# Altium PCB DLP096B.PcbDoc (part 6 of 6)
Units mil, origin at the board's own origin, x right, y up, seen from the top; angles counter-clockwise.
Board outline 4950 x 3159.45 mil, 8 copper layers (Top Layer, GND1, SIGNAL1, POWER1, POWER2, SIGNAL2, GND2, Bottom Layer), stack 60.4 mil thick; 327 components, 222 nets, 1374 pads, 853 vias.

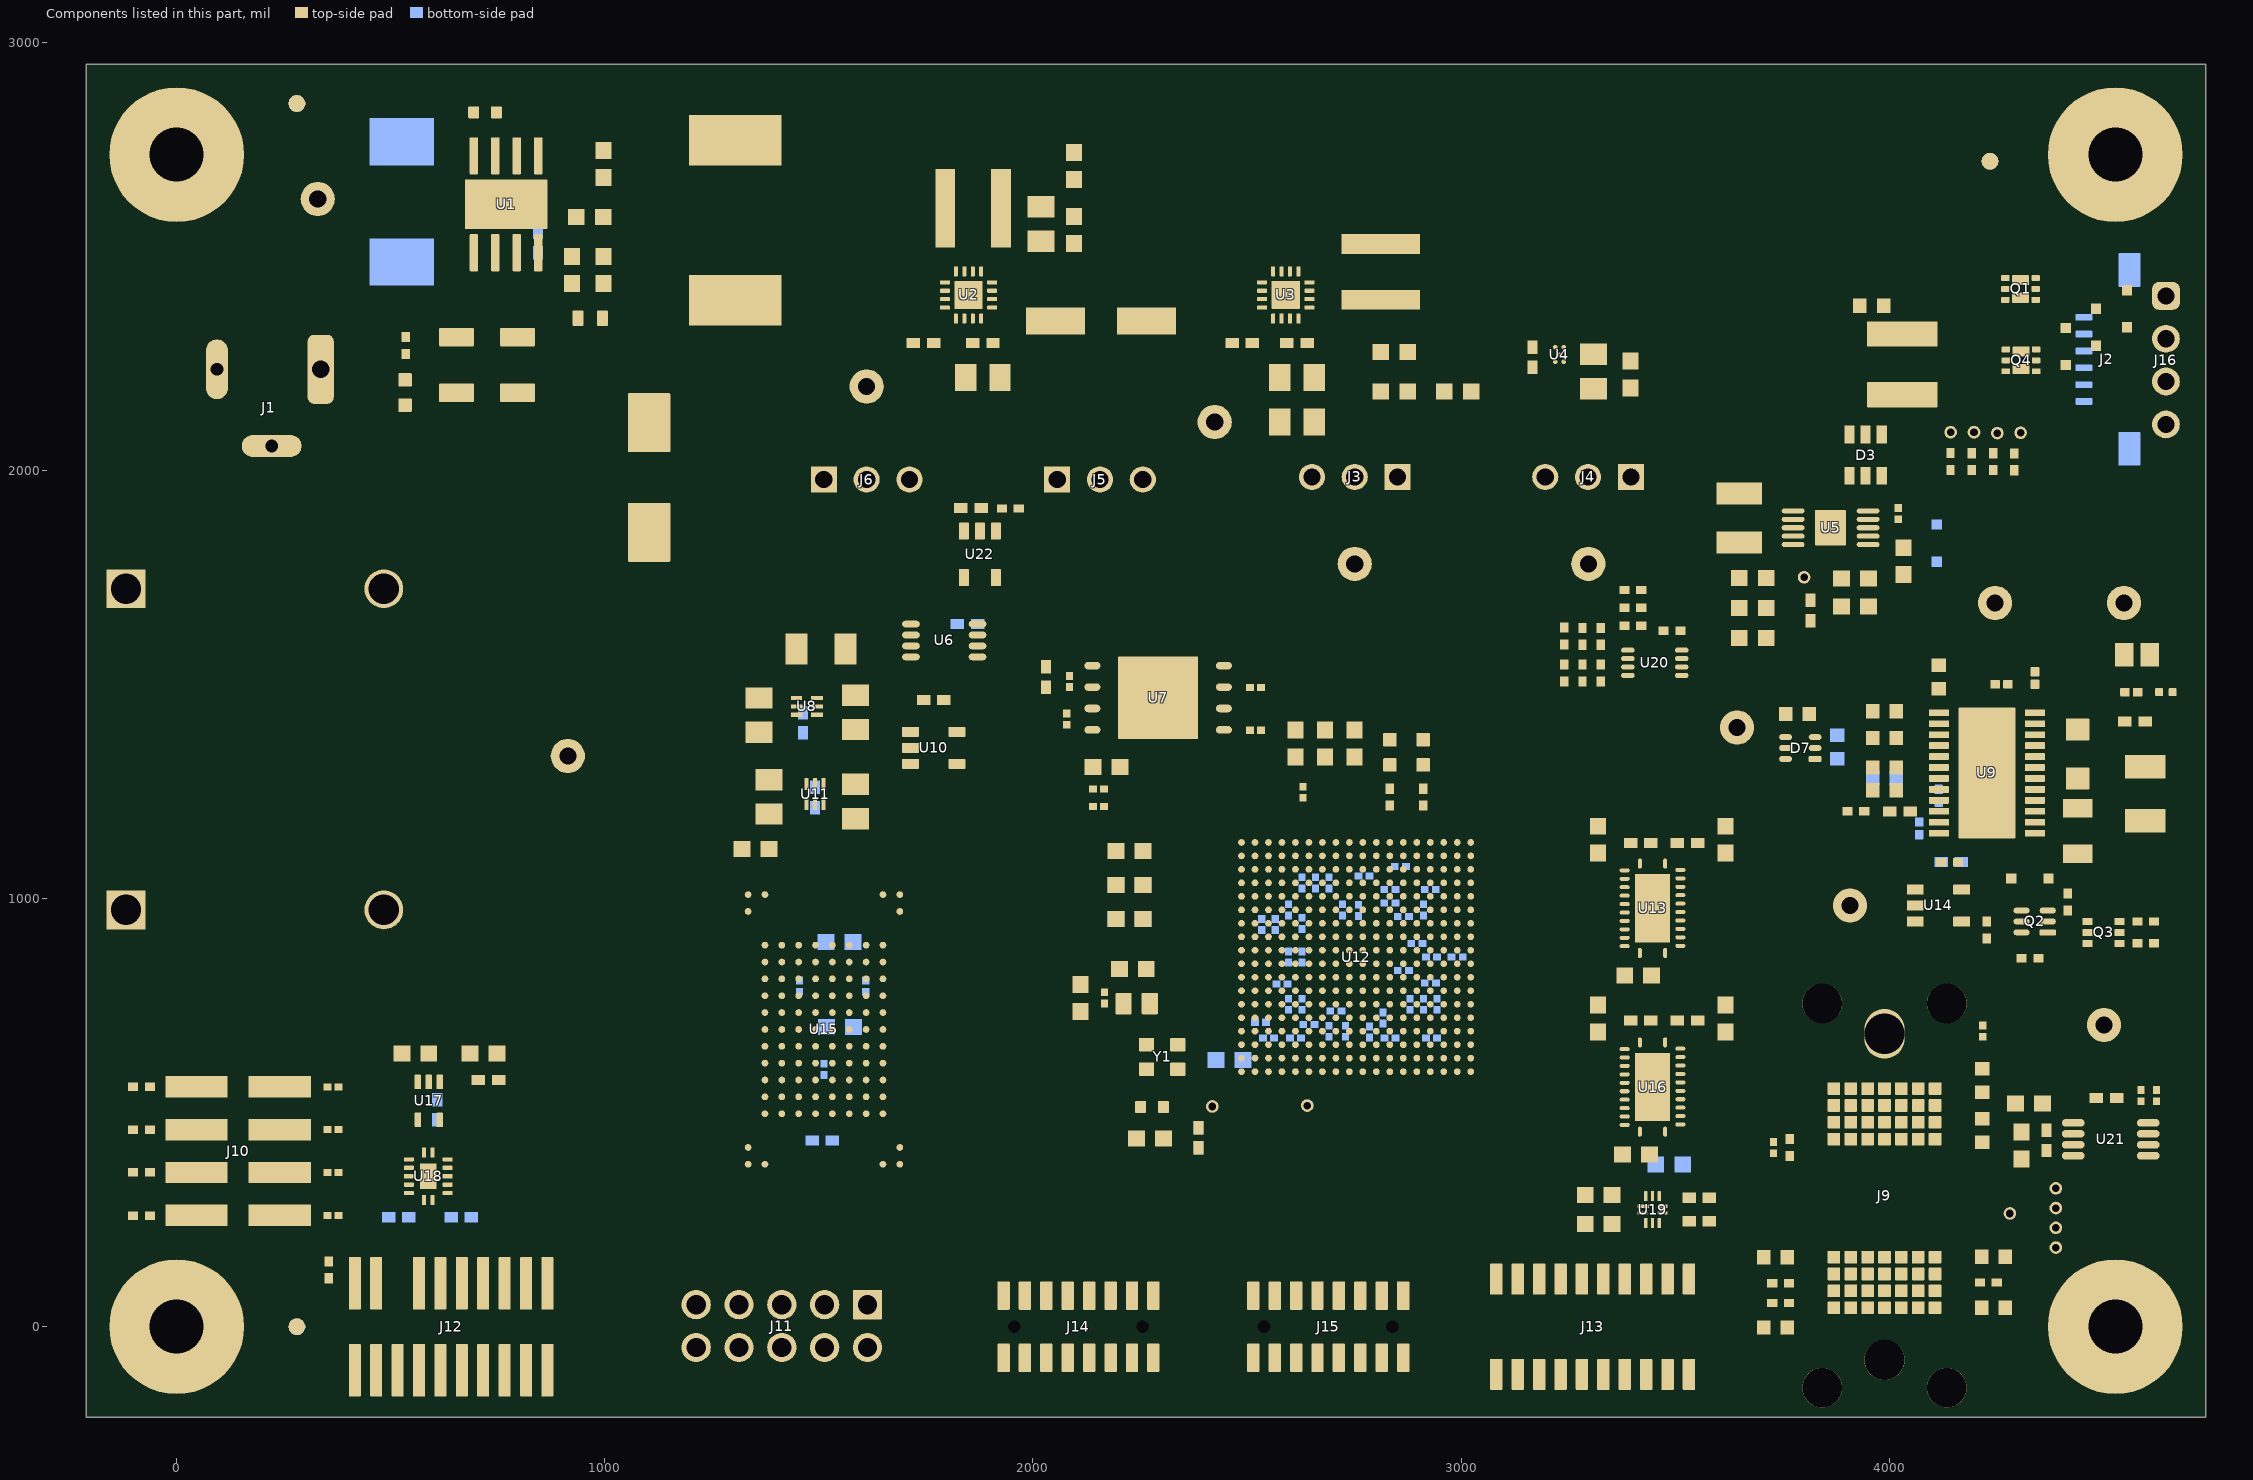
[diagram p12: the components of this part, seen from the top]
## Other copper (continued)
POWER1:
  pour cut-out: 531.25,2068.57 533.66,2068.71 536.04,2069.15 538.34,2069.87 541.6,2071.45 542.62,2072.11 543.59,2072.83 545.4,2074.43 546.23,2075.31 547,2076.24 548.37,2078.23 548.97,2079.28 549.49,2080.36 550.35,2082.62 550.68,2083.79 551.22,2087.37 551.26,2088.58 551.11,2090.99 550.93,2092.18 550.68,2093.37 550.35,2094.53 549.96,2095.67 549.49,2096.79 548.97,2097.88 548.37,2098.93 547.72,2099.94 547,2100.92 546.23,2101.85 544.52,2103.55 543.59,2104.33 542.62,2105.04 541.6,2105.7 540.55,2106.29 539.46,2106.82 538.34,2107.29 533.66,2108.44 531.25,2108.59 528.84,2108.44 525.3,2107.68 524.15,2107.29 521.95,2106.29 520.9,2105.7 519.88,2105.04 518.91,2104.33 517.1,2102.73 516.27,2101.85 515.5,2100.92 514.78,2099.94 513.53,2097.88 513,2096.79 512.54,2095.67 511.57,2092.18 511.28,2089.78 511.24,2088.58 511.39,2086.16 511.82,2083.79 512.54,2081.48 513,2080.36 513.53,2079.28 514.78,2077.21 516.27,2075.31 517.1,2074.43 517.98,2073.6 519.88,2072.11 520.9,2071.45 521.95,2070.86 524.15,2069.87 525.3,2069.47 526.46,2069.15 528.84,2068.71 530.04,2068.6
  pour cut-out: 531.25,1972.29 533.66,1972.44 536.04,1972.87 538.34,1973.59 541.6,1975.18 542.62,1975.83 543.59,1976.55 545.4,1978.15 546.23,1979.03 547,1979.96 548.37,1981.95 548.97,1983 549.49,1984.09 550.35,1986.35 550.68,1987.51 551.22,1991.09 551.26,1992.3 551.11,1994.71 550.93,1995.91 550.68,1997.09 550.35,1998.25 549.96,1999.4 549.49,2000.51 548.97,2001.6 548.37,2002.65 547.72,2003.67 547,2004.64 546.23,2005.57 544.52,2007.28 543.59,2008.05 542.62,2008.77 541.6,2009.42 540.55,2010.02 539.46,2010.55 538.34,2011.01 533.66,2012.16 531.25,2012.31 528.84,2012.16 525.3,2011.4 524.15,2011.01 521.95,2010.02 520.9,2009.42 519.88,2008.77 518.91,2008.05 517.1,2006.45 516.27,2005.57 515.5,2004.64 514.78,2003.67 513.53,2001.6 513,2000.51 512.54,1999.4 511.57,1995.91 511.28,1993.51 511.24,1992.3 511.39,1989.89 511.82,1987.51 512.54,1985.21 513,1984.09 513.53,1983 514.78,1980.93 516.27,1979.03 517.1,1978.15 517.98,1977.32 519.88,1975.83 520.9,1975.18 521.95,1974.58 524.15,1973.59 525.3,1973.2 526.46,1972.87 528.84,1972.44 530.04,1972.33
  pour cut-out: 525.76,530.44 528.17,530.58 530.55,531.02 532.85,531.74 536.11,533.32 537.12,533.98 538.1,534.69 539.91,536.3 540.73,537.18 541.51,538.1 542.88,540.09 543.47,541.15 544,542.23 544.86,544.49 545.18,545.66 545.73,549.24 545.77,550.44 545.62,552.86 545.44,554.05 545.18,555.23 544.86,556.4 544.47,557.54 544,558.66 543.47,559.74 542.88,560.8 542.22,561.81 541.51,562.78 540.73,563.71 539.03,565.42 538.1,566.2 537.12,566.91 536.11,567.57 535.06,568.16 533.97,568.69 532.85,569.15 528.17,570.31 525.76,570.45 523.34,570.31 519.8,569.55 518.66,569.15 516.46,568.16 515.41,567.57 514.39,566.91 513.42,566.2 511.61,564.59 510.78,563.71 510.01,562.78 509.29,561.81 508.04,559.74 507.51,558.66 507.05,557.54 506.08,554.05 505.78,551.65 505.75,550.44 505.89,548.03 506.33,545.66 507.05,543.35 507.51,542.23 508.04,541.15 509.29,539.08 510.78,537.18 511.61,536.3 512.49,535.47 514.39,533.98 515.41,533.32 516.46,532.73 518.66,531.74 519.8,531.34 520.97,531.02 523.34,530.58 524.55,530.47
  pour cut-out: 4164.06,1177.96 4164.06,1421.8 4178.52,1436.25 4271.31,1436.25 4292.31,1415.25 4292.31,1164.9 4277.78,1150.37 4228.17,1150.37 4228.13,1150.33 4227.5,1150.95 4177.9,1150.95 4163.91,1164.94 4163.91,1175.18
  pour cut-out: 2567.16,2413.07 2569.57,2413.22 2571.95,2413.65 2574.26,2414.37 2577.51,2415.96 2578.53,2416.61 2579.5,2417.33 2581.31,2418.93 2582.14,2419.81 2582.91,2420.74 2584.28,2422.73 2584.88,2423.78 2585.41,2424.87 2586.26,2427.13 2586.59,2428.29 2587.13,2431.87 2587.17,2433.08 2587.02,2435.49 2586.84,2436.69 2586.59,2437.87 2586.26,2439.03 2585.87,2440.17 2585.41,2441.29 2584.88,2442.38 2584.28,2443.43 2583.63,2444.45 2582.91,2445.42 2582.14,2446.35 2580.43,2448.06 2579.5,2448.83 2578.53,2449.55 2577.51,2450.2 2576.46,2450.8 2575.37,2451.33 2574.26,2451.79 2569.57,2452.94 2567.16,2453.09 2564.75,2452.94 2561.21,2452.18 2560.06,2451.79 2557.86,2450.8 2556.81,2450.2 2555.79,2449.55 2554.82,2448.83 2553.01,2447.23 2552.18,2446.35 2551.41,2445.42 2550.69,2444.45 2549.44,2442.38 2548.91,2441.29 2548.45,2440.17 2547.48,2436.69 2547.19,2434.29 2547.15,2433.08 2547.3,2430.67 2547.73,2428.29 2548.45,2425.98 2548.91,2424.87 2549.44,2423.78 2550.69,2421.71 2552.18,2419.81 2553.01,2418.93 2553.89,2418.1 2555.79,2416.61 2556.81,2415.96 2557.86,2415.36 2560.06,2414.37 2561.21,2413.98 2562.37,2413.65 2564.75,2413.22 2565.95,2413.11
  pour cut-out: 2567.16,2366.61 2569.57,2366.76 2571.95,2367.19 2574.26,2367.91 2577.51,2369.5 2578.53,2370.16 2579.5,2370.87 2581.31,2372.47 2582.14,2373.35 2582.91,2374.28 2584.28,2376.27 2584.88,2377.32 2585.41,2378.41 2586.26,2380.67 2586.59,2381.83 2587.13,2385.41 2587.17,2386.62 2587.02,2389.03 2586.84,2390.23 2586.59,2391.41 2586.26,2392.58 2585.87,2393.72 2585.41,2394.83 2584.88,2395.92 2584.28,2396.97 2583.63,2397.99 2582.91,2398.96 2582.14,2399.89 2580.43,2401.6 2579.5,2402.37 2578.53,2403.09 2577.51,2403.75 2576.46,2404.34 2575.37,2404.87 2574.26,2405.33 2569.57,2406.49 2567.16,2406.63 2564.75,2406.49 2561.21,2405.73 2560.06,2405.33 2557.86,2404.34 2556.81,2403.75 2555.79,2403.09 2554.82,2402.37 2553.01,2400.77 2552.18,2399.89 2551.41,2398.96 2550.69,2397.99 2549.44,2395.92 2548.91,2394.83 2548.45,2393.72 2547.48,2390.23 2547.19,2387.83 2547.15,2386.62 2547.3,2384.21 2547.73,2381.83 2548.45,2379.53 2548.91,2378.41 2549.44,2377.32 2550.69,2375.26 2552.18,2373.35 2553.01,2372.47 2553.89,2371.65 2555.79,2370.16 2556.81,2369.5 2557.86,2368.91 2560.06,2367.91 2561.21,2367.52 2562.37,2367.19 2564.75,2366.76 2565.95,2366.65
  pour cut-out: 2613.62,2366.61 2616.03,2366.76 2618.41,2367.19 2620.71,2367.91 2623.97,2369.5 2624.98,2370.16 2625.96,2370.87 2627.77,2372.47 2628.59,2373.35 2629.37,2374.28 2630.74,2376.27 2631.33,2377.32 2631.86,2378.41 2632.72,2380.67 2633.04,2381.83 2633.59,2385.41 2633.63,2386.62 2633.48,2389.03 2633.3,2390.23 2633.04,2391.41 2632.72,2392.58 2632.33,2393.72 2631.86,2394.83 2631.33,2395.92 2630.74,2396.97 2630.08,2397.99 2629.37,2398.96 2628.59,2399.89 2626.89,2401.6 2625.96,2402.37 2624.98,2403.09 2623.97,2403.75 2622.92,2404.34 2621.83,2404.87 2620.71,2405.33 2616.03,2406.49 2613.62,2406.63 2611.2,2406.49 2607.66,2405.73 2606.52,2405.33 2604.32,2404.34 2603.27,2403.75 2602.25,2403.09 2601.28,2402.37 2599.47,2400.77 2598.64,2399.89 2597.87,2398.96 2597.15,2397.99 2595.9,2395.92 2595.37,2394.83 2594.91,2393.72 2593.94,2390.23 2593.64,2387.83 2593.61,2386.62 2593.75,2384.21 2594.19,2381.83 2594.91,2379.53 2595.37,2378.41 2595.9,2377.32 2597.15,2375.26 2598.64,2373.35 2599.47,2372.47 2600.35,2371.65 2602.25,2370.16 2603.27,2369.5 2604.32,2368.91 2606.52,2367.91 2607.66,2367.52 2608.83,2367.19 2611.2,2366.76 2612.41,2366.65
  pour cut-out: 2613.62,2413.07 2616.03,2413.22 2618.41,2413.65 2620.71,2414.37 2623.97,2415.96 2624.98,2416.61 2625.96,2417.33 2627.77,2418.93 2628.59,2419.81 2629.37,2420.74 2630.74,2422.73 2631.33,2423.78 2631.86,2424.87 2632.72,2427.13 2633.04,2428.29 2633.59,2431.87 2633.63,2433.08 2633.48,2435.49 2633.3,2436.69 2633.04,2437.87 2632.72,2439.03 2632.33,2440.17 2631.86,2441.29 2631.33,2442.38 2630.74,2443.43 2630.08,2444.45 2629.37,2445.42 2628.59,2446.35 2626.89,2448.06 2625.96,2448.83 2624.98,2449.55 2623.97,2450.2 2622.92,2450.8 2621.83,2451.33 2620.71,2451.79 2616.03,2452.94 2613.62,2453.09 2611.2,2452.94 2607.66,2452.18 2606.52,2451.79 2604.32,2450.8 2603.27,2450.2 2602.25,2449.55 2601.28,2448.83 2599.47,2447.23 2598.64,2446.35 2597.87,2445.42 2597.15,2444.45 2595.9,2442.38 2595.37,2441.29 2594.91,2440.17 2593.94,2436.69 2593.64,2434.29 2593.61,2433.08 2593.75,2430.67 2594.19,2428.29 2594.91,2425.98 2595.37,2424.87 2595.9,2423.78 2597.15,2421.71 2598.64,2419.81 2599.47,2418.93 2600.35,2418.1 2602.25,2416.61 2603.27,2415.96 2604.32,2415.36 2606.52,2414.37 2607.66,2413.98 2608.83,2413.65 2611.2,2413.22 2612.41,2413.11
  pour cut-out: 1922.97,2133.39 1925.38,2133.53 1927.76,2133.97 1930.06,2134.69 1933.32,2136.27 1934.34,2136.93 1935.31,2137.65 1937.12,2139.25 1937.95,2140.13 1938.72,2141.06 1940.09,2143.05 1940.69,2144.1 1941.21,2145.18 1942.07,2147.44 1942.4,2148.61 1942.94,2152.19 1942.98,2153.4 1942.83,2155.81 1942.65,2157 1942.4,2158.19 1942.07,2159.35 1941.68,2160.49 1941.21,2161.61 1940.69,2162.7 1940.09,2163.75 1939.44,2164.76 1938.72,2165.74 1937.95,2166.67 1936.24,2168.37 1935.31,2169.15 1934.34,2169.86 1933.32,2170.52 1932.27,2171.11 1931.18,2171.64 1930.06,2172.11 1925.38,2173.26 1922.97,2173.41 1920.56,2173.26 1917.02,2172.5 1915.87,2172.11 1913.67,2171.11 1912.62,2170.52 1911.6,2169.86 1910.63,2169.15 1908.82,2167.55 1907.99,2166.67 1907.22,2165.74 1906.5,2164.76 1905.25,2162.7 1904.72,2161.61 1904.26,2160.49 1903.29,2157 1903,2154.6 1902.96,2153.4 1903.11,2150.99 1903.54,2148.61 1904.26,2146.3 1904.72,2145.18 1905.25,2144.1 1906.5,2142.03 1907.99,2140.13 1908.82,2139.25 1909.7,2138.42 1911.6,2136.93 1912.62,2136.27 1913.67,2135.68 1915.87,2134.69 1917.02,2134.29 1918.18,2133.97 1920.56,2133.53 1921.76,2133.42
  pour cut-out: 1947.7,2262.04 1950.11,2262.19 1952.48,2262.62 1954.79,2263.34 1958.05,2264.93 1959.06,2265.58 1960.04,2266.3 1961.84,2267.9 1962.67,2268.78 1963.45,2269.71 1964.82,2271.7 1965.41,2272.75 1965.94,2273.84 1966.8,2276.1 1967.12,2277.26 1967.67,2280.84 1967.71,2282.05 1967.56,2284.46 1967.38,2285.66 1967.12,2286.84 1966.8,2288 1966.4,2289.15 1965.94,2290.26 1965.41,2291.35 1964.82,2292.4 1964.16,2293.42 1963.45,2294.39 1962.67,2295.32 1960.96,2297.03 1960.04,2297.8 1959.06,2298.52 1958.05,2299.17 1956.99,2299.77 1955.91,2300.3 1954.79,2300.76 1950.11,2301.91 1947.7,2302.06 1945.28,2301.91 1941.74,2301.15 1940.6,2300.76 1938.4,2299.77 1937.34,2299.17 1936.33,2298.52 1935.36,2297.8 1933.55,2296.2 1932.72,2295.32 1931.95,2294.39 1931.23,2293.42 1929.98,2291.35 1929.45,2290.26 1928.99,2289.15 1928.01,2285.66 1927.72,2283.26 1927.69,2282.05 1927.83,2279.64 1928.27,2277.26 1928.99,2274.95 1929.45,2273.84 1929.98,2272.75 1931.23,2270.68 1932.72,2268.78 1933.55,2267.9 1934.43,2267.07 1936.33,2265.58 1937.34,2264.93 1938.4,2264.33 1940.6,2263.34 1941.74,2262.95 1942.91,2262.62 1945.28,2262.19 1946.49,2262.08
  pour cut-out: 1416.04,1418.24 1418.45,1418.39 1420.83,1418.82 1423.14,1419.54 1426.39,1421.12 1427.41,1421.78 1428.38,1422.5 1430.19,1424.1 1431.02,1424.98 1431.79,1425.91 1433.17,1427.9 1433.76,1428.95 1434.29,1430.04 1435.15,1432.3 1435.47,1433.46 1436.01,1437.04 1436.05,1438.25 1435.91,1440.66 1435.72,1441.86 1435.47,1443.04 1435.15,1444.2 1434.75,1445.34 1434.29,1446.46 1433.76,1447.55 1433.17,1448.6 1432.51,1449.61 1431.79,1450.59 1431.02,1451.52 1429.31,1453.23 1428.38,1454 1427.41,1454.72 1426.39,1455.37 1425.34,1455.97 1424.25,1456.49 1423.14,1456.96 1418.45,1458.11 1416.04,1458.26 1413.63,1458.11 1410.09,1457.35 1408.95,1456.96 1406.74,1455.97 1405.69,1455.37 1404.68,1454.72 1403.7,1454 1401.89,1452.4 1401.07,1451.52 1400.29,1450.59 1399.57,1449.61 1398.32,1447.55 1397.8,1446.46 1397.33,1445.34 1396.36,1441.86 1396.07,1439.46 1396.03,1438.25 1396.18,1435.84 1396.61,1433.46 1397.33,1431.15 1397.8,1430.04 1398.32,1428.95 1399.57,1426.88 1401.07,1424.98 1401.89,1424.1 1402.77,1423.27 1404.68,1421.78 1405.69,1421.12 1406.74,1420.53 1408.95,1419.54 1410.09,1419.15 1411.25,1418.82 1413.63,1418.39 1414.83,1418.28
  pour cut-out: 2163.93,504.84 2163.93,423.37 2182.57,423.37 2186.04,426.84 2186.04,482.73
  pour cut-out: 4251.1,843.02 4204.31,843.02 4204.5,843.21 4204.5,851.48 4204.92,851.9 4251.14,851.9
  text "4" at 2588.44,2743.77 h60
  text "POWER1" at 376.89,-1071.84 h60
POWER2:
  text "5" at 2588.44,2743.77 h60
  text "POWER2" at 371.65,-1073.59 h60
Bottom Layer:
  text "8" at 2588.44,2743.77 h60
  text ".Layer_Name" at 366,-1069.49 h60

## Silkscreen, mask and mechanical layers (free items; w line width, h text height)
Top Overlay:
  circle w10: c1879.46,2490.68 r1.81
  circle w10: c4380.04,1152.3 r4.87
  circle w10: c2619.42,2494.23 r3
  circle w10: c693.58,2446.43 r4.87
  circle w10: c4536.63,865.5 r3
  circle w10: c3531.53,-166.36 r4.87
  circle w15: c-96.35,2453.46 r10
  circle w10: c4439.56,1444.76 r4.87
  circle w10: c3982.04,2122.81 r4.87
  lines w6.1: 883.26,2385.63 959.52,2385.63 969.69,2395.8 ; 3786.67,977.78 3840.7,977.78 ; 4567.9,706.4 4637.9,706.4
  lines w6.5: 2004.06,738.47 2013.27,729.27 2070.31,729.27 ; 2750,1903.55 2750,1925.06 ; 3295,1903.55 3295,1925.06 ; 3924.39,1326.74 3924.39,1311.86 3932.25,1304 ; 3937.71,1528.63 3929.11,1520.03 3929.11,1473.96 3939.91,1463.15 ; 3944.99,1564.84 3963.78,1583.63 3963.78,1642.19 ; 4238.32,13.92 4238.32,-94.35 4252.17,-108.21
  text "'.PRJ_Number'.PCB_Rev" at 3681.49,2682.51 h108.27
  text "12V" at 286.81,2529.82 h30
  text "LED" at 4600.93,2471.4 h30
  text "R" at 4588.17,2278.75 h30 r90
  text "12V" at 379.08,2243.8 h30
  text "+" at 1171.78,2200.63 h70
  text "G" at 4588.17,2185.05 h30 r90
  text "S_EN" at 4170.21,2107.79 h23 r90
  text "R_EN" at 4213.37,2107.79 h23 r90
  text "B_EN" at 4256.54,2107.79 h23 r90
  text "G_EN" at 4299.71,2107.79 h23 r90
  text "B" at 4588.17,2092.67 h30 r90
  text "5V" at 1583.7,2091.55 h30
  text "3V3" at 2378.07,2010.42 h30
  text "GND" at 2587.39,1940.16 h30 r90
  text "GND" at 3136.28,1934.41 h30 r90
  text "1V2_OB" at 2957.89,1897.16 h30 r90
  text "1V2_EXT" at 2644.1,1850.85 h30
  text "1.8V_DMD_EXT" at 3090.98,1850.3 h30
  text "GND" at 2275.45,1826.96 h30 r90
  text "GND" at 1729.49,1826.09 h30 r90
  text "1.8V_DMD_OB" at 3503.43,1825.38 h30 r90
  text "5V_OB" at 1533.14,1768.43 h30 r90
  text "VOFFSET" at 4452.84,1755.46 h30
  text "VBIAS" at 4176.38,1752.8 h30
  text "1V8" at 3142.01,1747.75 h30
  text "3V3_OB" at 2078.11,1739.03 h30 r90
  text "1V2" at 2821.2,1738.15 h30
  text "5V_EXT" at 1633.96,1736.12 h30 r90
  text "3V3_EXT" at 2178.85,1709.05 h30 r90
  text "IADJ" at 3783.72,1703.31 h23 r90
  text "12V" at 636.8,1698.44 h30
  text "GND" at 869.1,1403.45 h30
  text "VRESET" at 3554.64,1295.64 h30
  text "A" at 3066.32,1118.55 h30
  text "A" at 1802.21,1000.49 h30
  text "E" at 3066.32,993.3 h30
  text "GND" at 635.36,959.96 h30
  text "A" at 3863.59,832.07 h30
  text "B" at 3902.96,832.07 h30
  text "C" at 3942.33,832.07 h30
  text "D" at 3981.7,832.07 h30
  text "E" at 4021.07,832.07 h30
  text "F" at 4060.44,832.07 h30
  text "G" at 4099.81,832.07 h30
  text "K" at 3062.16,831.38 h30
  text "F" at 1804.47,805.59 h30
  text "DMD_POWER_EN" at 3783.67,786.95 h30 r90
  text "R" at 3063.9,676.33 h30
  text "2" at 4183.3,636.69 h30
  text "BOOT SW" at 62.35,632.09 h30
  text "L" at 1800.53,599.95 h30
  text "V" at 3063.9,577.05 h30
  text "1" at 2494.59,539.41 h30 r90
  text "5" at 2627.02,534.41 h30 r90
  text "10" at 2787.48,509.42 h30 r90
  text "15" at 2945.96,509.42 h30 r90
  text "18" at 3035.63,509.42 h30 r90
  text "DMD_DISCHARGE_EN" at 4696.08,458.01 h30 r90
  text "VSYS_MON" at 2437.94,428.83 h23
  text "U" at 1801.98,365.8 h30
  text "5" at 1484.52,297.06 h30
  text "10" at 1668.55,295.61 h30
  text "1" at 1327.98,295.09 h30
  text "CHEETAH SPI" at 1008.96,204.16 h30
  text "Host Interfaces Ext" at 1839.97,196.44 h30
  text "MCU_JTAG" at 525.62,185.47 h30
  text "UART" at 1957.26,141.71 h23
  text "I2C" at 2170.7,141.71 h23
  text "15" at 4179.85,-22.74 h30
  text "GPMC NAND" at 3034.73,-106.99 h30 r90
  text "ENET RMII" at 2462.31,-125.5 h30 r90
  text "LIN" at 1968.61,-177.98 h23
  text "CAN" at 2174.55,-177.98 h23
  text ".Layer_Name" at 366,-1069.49 h60
Bottom Overlay:
  circle w6: c814.97,657.14 r30
  circle w6: c2518.15,773.17 r30
  circle w6: c3168.33,1634.16 r35.79
  circle w6: c2810.54,867.54 r35.79
  circle w6: c2940.69,1084.07 r35.79
  circle w6: c3019.28,1758.86 r35.79
  lines w6.1: 1606.15,323.73 1618.25,311.63 2366.59,311.63 2437.83,382.88 2437.83,412.37 ; 1856.23,271.65 1874.92,290.34 2443.32,290.34 2500.02,347.04 ; 2545.44,1479.14 3076.06,1479.14 3076.06,1844.14 2545.44,1844.14 2545.44,1479.14 ; 2763.71,596.69 2763.71,914.6 3028.72,914.6 3028.72,596.69 2763.71,596.69 ; 3113.42,1230.44 3534.9,1230.44 3534.9,1694.31 3113.42,1694.31 3113.42,1230.44
  lines w6.5: 2343.94,907.34 2355.79,895.49 2511.54,895.49 2525.01,908.96 ; 2502.83,674.47 2480.18,697.12 2480.18,841.53 2520.07,881.42 2545.47,906.82 2750.32,906.82 2750.32,715.95 ; 2537.93,657.75 2741.39,657.75 2749.23,665.6 ; 2565.11,1039.03 2607.03,1039.03 ; 2644.27,1124.6 2644.27,1071.06 2648.73,1065.59 ; 759.47,468.68 759.47,973.06 1265.3,973.06 1265.3,468.68 759.47,468.68 ; 2676.36,940.39 2676.36,1131.4 2988.4,1131.4 2988.4,940.39 2676.36,940.39
  text "B" at 3027.97,1744.87 h30
  text "A" at 3178.08,1623.04 h30
  text "B" at 2949.37,1070.08 h30
  text "A" at 2820.32,853.2 h30
  text "C" at 2525.25,758.44 h30
  text "C" at 824.25,642.61 h30
  text ".Layer_Name" at 366,-1069.49 h60
Top Paste:
  text ".Layer_Name" at 366,-1069.49 h60
Bottom Paste:
  text ".Layer_Name" at 366,-1069.49 h60
Top Solder:
  text ".Layer_Name" at 366,-1069.49 h60
  text ".Layer_Name" at 366,-1069.49 h60
Bottom Solder:
  text ".Layer_Name" at 366,-1069.49 h60
Drill Guide:
  text ".Layer_Name" at 366,-1069.49 h60
M1 Board Outline:
  lines w10: -211,-211 -211,2948.45 4739,2948.45 4739,-211 -211,-211
  lines w47.24: -211,-211 -211,2948.45 4739,2948.45 4739,-211 -211,-211 ; 3851.09,217.59 ccw(c3866.84,217.59) 3866.84,201.85 4110.93,201.85 ccw(c4110.93,217.59) 4126.68,217.59 4126.68,382.95 ccw(c4110.93,382.95) 4110.93,398.7 3866.84,398.7 ccw(c3866.84,382.95) 3851.09,382.95 3851.09,217.59
  text "CUTOUT" at 3901.4,248.13 h30
  text ".Layer_Name" at 366,-1069.49 h60
M2 Board Dimensions:
  rectangle: 4839.9,-147.52 4964.9,-22.52
  rectangle: 4964.9,-272.52 5339.9,-147.52
  lines w7: 4839.9,-147.52 5839.9,-147.52 ; 4964.9,-272.52 4964.9,-22.52 ; 5089.9,-272.52 5089.9,-22.52 ; 5339.9,-272.52 5339.9,-22.52 ; 5589.9,-272.52 5589.9,-22.52 ; 4839.9,-272.52 5839.9,-272.52 5839.9,-22.52 4839.9,-22.52 4839.9,-272.52
  lines w10: -211,-211 4739,-211 4739,2948.45 -211,2948.45 -211,-211
M3 3D STEP Top:
  text ".Layer_Name" at 366,-1069.49 h60
M4 3D STEP Bottom:
  text ".Layer_Name" at 366,-1069.49 h60
M5 Assembly Top:
  circle w2: c4143.43,2089.2 r13.63
  circle w2: c4197.91,2089.2 r13.63
  circle w2: c4252.38,2087.15 r13.63
  circle w2: c4306.86,2087.97 r13.63
  circle w5: c693.91,2474.79 r4.82
  circle w10: c1214.61,1009.18 r5.16
  circle w10: c2428.46,1372.93 r12.89
  circle w10: c2438.83,1131.11 r5.45
  circle w10: c1750.3,1396.72 r2.8
  circle w10: c2289.22,-44.55 r10.59
  circle w10: c2872.18,-44.05 r11.92
  circle w10: c3870.88,662.49 r4.25
  circle w10: c3537.37,-76.24 r13.63
  circle w10: c4093.94,1029.87 r1.85
  circle w10: c4354.39,918.45 r2.33
  circle w10: c3219.35,2288.22 r1.33
  circle w10: c-65,2457.17 r12.26
  circle w10: c620.97,544.94 r1.81
  circle w10: c598.22,302.19 r1.63
  circle w10: c220.03,260.82 r8.63
  circle w10: c415.01,-72.87 r11.68
  rectangle: 3371.78,1959.73 3424.57,2010.65
  rectangle: 2827.38,1960.2 2880.16,2011.12
  rectangle: 2029.75,1954.35 2082.54,2005.27
  rectangle: 1484.75,1954.35 1537.54,2005.27
  lines w5: 3204.84,2239.53 3204.84,2302.05 3254.46,2302.05 3254.46,2239.53 3204.84,2239.53
  lines w6.1: 5590.34,2153.55 6590.58,2153.55 ; 5590.34,2228.55 6591.41,2228.55 ; 5590.34,2303.55 6591.41,2303.55 ; 5590.34,2378.55 6591.28,2378.55 ; 5590.34,2453.55 6590.17,2453.55 ; 5946.27,2078.55 5946.27,2553.55 ; 5590.34,2078.55 5590.34,2553.55 6592.35,2553.55 6592.35,2078.55 5590.34,2078.55
  lines w6.5: 681.08,2462.25 681.08,2780.49 859.41,2780.49 859.41,2462.25 681.08,2462.25
  lines w10: -503,-1141.17 6097,-1141.17 ; -503,-937.83 6099,-937.83 ; -503,-734.5 -503,-1344.5 3502,-1344.5 6099,-1344.5 6099,-734.5 -502.5,-734.5 -502.5,-1344.5 1073,-1344.5 ; 1962,-1344.5 1962,-734.5 ; 3229,-937.83 3229,-734.5 ; 3809.41,1321.42 cw(c3808.6,1321.42) 3809.39,1321.62 ; 4069,-937.83 4069,-734.5 ; 4691,-1351 4691,-1148.17
  text "U1" at 756.26,2613.87 h20
  text "Jumper stuff list table for DLP2021Q1PRU-DVH" at 5477.66,2603.4 h30
  text "Ref Des" at 5653.13,2489.39 h35
  text "Position" at 6142.56,2489.39 h35
  text "J3" at 5741.85,2399.68 h30
  text "1-2" at 6230.44,2399.68 h30
  text "K" at 4139.37,2361.8 h20
  text "J4" at 5741.85,2324.68 h30
  text "1-2" at 6230.44,2324.68 h30
  text "J5" at 5741.85,2249.68 h30
  text "1-2" at 6230.44,2249.68 h30
  text "+" at 1084.14,2198.94 h60
  text "J6" at 5741.85,2174.68 h30
  text "1-2" at 6230.44,2174.68 h30
  text "K" at 526.21,2120.34 h20
  text "TP3" at 4200.88,2114.16 h20 r90
  text "TP14" at 4286.8,2112.81 h20 r90
  text "TP15" at 4245.96,2111.95 h20 r90
  text "TP2" at 4162.06,2109.31 h20 r90
  text "1-2, 3-4, 5-6, 7-8" at 6005.52,2103.01 h30
  text "J10" at 5729.36,2099.68 h30
  text "K" at 4435.38,1431.31 h20
  text "K" at 2827.81,1380.59 h20
  text "K" at 2905,1379.47 h20
  text "K" at 4224.96,1035.44 h20
  text "COMPONENTS MARKED 'DNP' SHOULD NOT BE POPULATED." at 942.5,-529.5 h60
  text "ASSEMBLY VARIANT:" at 942,-645 h60
  text ".VariantName" at 1978,-645 h60
  text "PCB VIEWED FROM TOP SIDE" at -439.5,-866.67 h60
  text "BOARD #:" at 2037,-866.67 h60
  text ".PRJ_Number" at 2582.5,-866.67 h60
  text "REV:" at 3427,-866.67 h60
  text ".PCB_Rev" at 3718.5,-866.67 h60
  text "SVN REV:" at 4265,-866.67 h60
  text ".VersionControl_RevNumber" at 4771,-866.67 h60
  text "TID #:" at 2037,-1070 h60
  text ".TID" at 2582.5,-1070 h60
  text "PLOT NAME =" at -439.5,-1275.34 h60
  text ".plot_File_Name" at 366,-1275.34 h60
  text "GENERATED    :" at 2039,-1275.34 h60
  text ".Print_Date" at 2908.5,-1275.34 h60
  text ".Print_Time" at 3637.5,-1275.34 h60
  text "TEXAS INSTRUMENTS" at 4902,-1275.34 h60
M6 Assembly Bottom:
  lines w10: -503.5,-938.33 6098.5,-938.33 ; -501.5,-1141.67 6098.5,-1141.67 ; 904.5,-1351.5 904.5,-1148.67 ; 1526.5,-938.33 1526.5,-735 ; 2366.5,-938.33 2366.5,-735 ; 3633.5,-1345 3633.5,-735 ; 4522.5,-1345 6098,-1345 6098,-735 -503.5,-735 -503.5,-1345 2093.5,-1345 6098.5,-1345 6098.5,-735
  text "COMPONENTS MARKED 'DNP' SHOULD NOT BE POPULATED." at 5891,-529 h60
  text ".VariantName" at 4847,-645 h60
  text "ASSEMBLY VARIANT:" at 5886,-645 h60
  text ".VersionControl_RevNumber" at 824.5,-867.17 h60
  text "SVN REV:" at 1330.5,-867.17 h60
  text ".PCB_Rev" at 1877,-867.17 h60
  text "REV:" at 2168.5,-867.17 h60
  text ".PRJ_Number" at 3013,-867.17 h60
  text "BOARD #:" at 3558.5,-867.17 h60
  text "PCB VIEWED FROM BOTTOM SIDE" at 6035,-867.17 h60
  text ".TID" at 3013,-1070.5 h60
  text "TID #:" at 3558.5,-1070.5 h60
  text "TEXAS INSTRUMENTS" at 693.5,-1275.84 h60
  text ".Print_Time" at 1958,-1275.84 h60
  text ".Print_Date" at 2687,-1275.84 h60
  text "GENERATED    :" at 3556.5,-1275.84 h60
  text ".plot_File_Name" at 5229.5,-1275.84 h60
  text "PLOT NAME =" at 6035,-1275.84 h60
M9 Title Sheet:
  drawing of 57 lines, arcs and shapes, not listed
  text "1" at 528.84,7825.5 h70
  text "2" at 3024.5,7825.5 h70
  text "3" at 5513.84,7825.5 h70
  text "4" at 8020.51,7825.5 h70
  text "5" at 10519.5,7825.5 h70
  text "6" at 13024.5,7825.5 h70
  text "A" at -627.5,6682.5 h70
  text "A" at 14172.5,6682.5 h70
  text "B" at -627.5,4302.5 h70
  text "B" at 14172.5,4302.5 h70
  text "C" at -627.5,1927.5 h70
  text "C" at 14172.5,1927.5 h70
  text "PROJECT TITLE:" at 11132.5,66.5 h45
  text ".PRJ_Title" at 11182.5,-66.83 h70
  text "DESIGNED FOR:" at 11132.5,-234.5 h45
  text ".PRJ_Customer" at 11182.5,-374.5 h70
  text "D" at -627.5,-442.5 h70
  text "D" at 14172.5,-442.5 h70
  text "FILE NAME:" at 11132.5,-534.5 h45
  text ".PCB_File_Name_No_Path" at 11182.5,-654.5 h70
  text "Texas Instruments (TI) and/or its licensors do not warrant the accuracy or completeness of this specification" at 6163,-816.34 h45
  text "ENGINEER:" at 11132.5,-824.5 h45
  text "LAYOUT BY:" at 12637.5,-824.5 h45
  text "or any information contained therein. TI and/or its licensors do not warrant that this design will meet" at 6118.01,-929 h45
  text ".PRJ_Engineer" at 11182.5,-979.49 h70
  text ".PCB_Layout" at 12688,-979.49 h70
  text "the specifications, will be suitable for your application or fit for any particular purpose, or will operate in" at 6118.01,-1041.67 h45
  text "ALTIUM DESIGNER VERSION:" at 12637.5,-1134.5 h45
  text "an implementation. TI and/or its licensors do not warrant that the design is production worthy. You should" at 6118.01,-1154.33 h45
  text "completely validate and test your design implementation to confirm the system functionality for your application." at 6163,-1267 h45
  text ".print_Scale" at 11182.5,-1267.83 h70
  text ".Application_BuildNumber" at 12688,-1267.83 h70
  text "1" at 528.84,-1474.5 h70
  text "2" at 3024.5,-1474.5 h70
  text "3" at 5513.84,-1474.5 h70
  text "4" at 8020.51,-1474.5 h70
  text "5" at 10519.5,-1474.5 h70
  text "6" at 12065.46,-1480.85 h70
  text "WO# : 309481 - 9479-D" at 12561.41,-1481.02 h70
M10 Fab Notes:
  drawing of 203 lines, arcs and shapes, not listed
  text "FAB NOTES :" at -262.62,7503.09 h80
  text "1.  BOARD DIMENSION : 125.73MM X 80.25MM." at -105.99,7237.15 h80
  text "2. VENDOR MAY ADJUST SOLDERMASK WHEREVER SOLDERMASK PADS ARE THE SAME SIZE (1:1) AS PER THE MANUFACTURING CAPABILITIES AND" at -102.63,7001.58 h80
  text "ALL OTHER SOLDER MASK PADS SHALL NOT BE MODIFIED, PROVIDED NO ADJACENT COPPER IS EXPOSED AND NO CONFLICT IS PRODUCED WITH ANY STATED \"VIA TENTING/COVERING\" REQUIREMENTS." at 129.91,6836.27 h80
  text "3. ALL VIAS ARE TENTED ON BOTH SIDES UNLESS OTHERWISE SOLDER MASK IS OPENED IN GERBER." at -102.63,6661.33 h80
  text "4. TRACES WITH 6.5MIL TO BE 50 OHMS +/-10% SINGLE ENDED ON TOP LAYER, SIGNAL1, SIGNAL2 & BOTTOM LAYER (L1,L3,L6 & L8)." at -102.63,6483.62 h80
  text "5. 8.02MIL VIAS NEED TO BE FILLED WITH NON-CONDUCTIVE EPOXY-RESIN AND OVERPLATE WITH COPPER. SURFACE MUST BE FLAT," at -100.72,6269.39 h80
  text "DESIGN INFORMATION" at 12171.02,6145.17 h60
  text "FLATNESS TOLERANCE IS +0.000/-0.001\" ON TOP SIDE ONLY AND +0.000/-0.003\" ON BOTTOM SIDE." at 136.97,6078.42 h80
  text "MIN. TRACK WIDTH:" at 11526.46,6013.05 h60
  text "5" at 12622.7,6013.05 h60
  text "MIL" at 12777.46,6013.05 h60
  text "MINIMUM ANNULAR RING REQUIREMENT IS WAIVED FOR FILLED VIAS." at 133.68,5906.93 h80
  text "5" at 12619.35,5895.9 h60
  text "MIN. CLEARANCE:" at 11526.46,5888.92 h60
  text "MIL" at 12777.46,5888.92 h60
  text "19.685" at 12425.36,5767.1 h60
  text "MIN. VIA PAD SIZE:" at 11526.46,5764.8 h60
  text "MIL" at 12777.46,5764.8 h60
  text "6. 8.01MIL VIAS NEED TO BE FILLED WITH NON-CONDUCTIVE EPOXY-RESIN AND OVERPLATE WITH COPPER. SURFACE MUST BE FLAT," at -92.06,5714.26 h80
  text "0.05mm (2MIL)" at 12221.46,5634.9 h60
  text "MINIMUM ANNULAR RING" at 11197.23,5626.67 h60
  text "EXTERNAL" at 12929.46,5626.67 h60
  text "FLATNESS TOLERANCE IS +0.000/-0.001\" ON BOTTOM SIDE ONLY AND +0.000/-0.003\" ON TOP SIDE." at 143.57,5524.37 h80
  text "PER" at 11397.23,5516.55 h60
  text "IPC-D-275 CLASS 2 LEVEL C" at 11617.23,5516.54 h60
  text "MIL, HOLES" at 13105.46,5416.07 h60
  text "+/-" at 12713,5407.48 h60
  text "+/-" at 13567,5407.48 h60
  text "REGISTRATION TOLERANCES:" at 11197.23,5406.42 h60
  text "METAL" at 12397,5406.42 h60
  text "5" at 12973.2,5406.42 h60
  text "3" at 13806.2,5406.42 h60
  text "MIL" at 13922.46,5406.42 h60
  text "MINIMUM ANNULAR RING REQUIREMENT IS WAIVED FOR FILLED VIAS." at 143.57,5349.58 h80
  text "HOLE SIZE TOLERANCE (UNLESS OTHERWISE SPECIFIED):" at 11197.23,5308.1 h60
  text "+/-" at 13567,5305.23 h60
  text "3" at 13806.2,5304.17 h60
  text "MIL" at 13922.46,5304.17 h60
  text "MATERIAL:" at 11122.46,5166.52 h60
  text "FR-4 High Tg" at 12108.9,5038 h60
  text "X" at 11964.46,5030.01 h60
  text "FR-408" at 11543.46,5025.49 h60
  text "OTHER" at 13031.46,5025.49 h60
  text "62 MIL (1.6mm) +/-10%" at 11863.56,4882.46 h60
  text "X" at 11743.46,4880.01 h60
  text "THICKNESS:" at 11197.23,4874.24 h60
  text "OTHER" at 13148.46,4874.24 h60
  text "TOLERANCE:" at 11197.23,4735.92 h60
  text "X" at 12045.46,4735.92 h60
  text "ANSI IPC-6012 TYPE 3 CLASS 2" at 12223.48,4735.92 h60
  text "OTHER +/-" at 12223.46,4591.73 h60
  text "BOW & TWIST:" at 11197.23,4446.54 h60
  text "X" at 12045.46,4446.54 h60
  text "ANSI IPC-6012 TYPE 3 CLASS 2" at 12223.48,4446.54 h60
  text "OTHER +/-" at 12223.46,4299.85 h60
  text "DRILLING:" at 11122.46,4169.23 h60
  text "NC_DRILL FILES" at 12883.46,4064.04 h60
  text "REFERENCE:" at 11197.23,4060.1 h60
  text "X" at 11854.46,4060.01 h60
  text "AS SHOWN" at 12032.46,4060.1 h60
  text "X" at 12755.46,4060.1 h60
  text "OTHER" at 13181.46,3917.85 h60
  text "PTH COPPER THICKNESS:" at 11196.91,3914.32 h60
  text "X" at 12336.14,3914.32 h60
  text "20-30 um" at 12464.14,3914.32 h60
  text "BOARD FINISH:" at 11122.46,3766.73 h60
  text "SILKSCREEN:" at 11277.68,3656.6 h60
  text "X" at 12235.46,3656.6 h60
  text "TOP" at 12352.46,3656.6 h60
  text "X" at 12745.46,3656.6 h60
  text "BOTTOM" at 12863.46,3656.6 h60
  text "SILKSCREEN COLOR:" at 11277.68,3501.41 h60
  text "X" at 12234.46,3501.41 h60
  text "WHITE" at 12352.46,3501.41 h60
  text "OTHER" at 12863.46,3501.41 h60
  text "X" at 12365.46,3357.96 h60
  text "GREEN" at 12483.46,3357.96 h60
  text "OTHER" at 13101.46,3357.96 h60
  text "SOLDER RESIST COLOR:" at 11277.68,3351.1 h60
  text "X" at 12957.46,3205.23 h60
  text "MATTE" at 12483.46,3203.71 h60
  text "SEMI-GLOSS" at 13101,3203.07 h60
  text "IMMERSION GOLD (ENIG)" at 12183.46,3030.94 h60
  text "ENEPIG" at 13521,3023.72 h60
  text "SURFACE FINISH:" at 11122.46,3022.72 h60
  text "X" at 12005.46,3022.72 h60
  text "IMM. TIN/SILVER OR EQUIV" at 11452,2885.4 h60
  text "OTHER" at 12883.46,2881.47 h60
  text "ARRAY/PANEL:" at 11122.46,2726.09 h60
  text "CUT AND TRIM PER M1 BOARD OUTLINE" at 12183.46,2717.87 h60
  text "N.C. ROUTE" at 12183.46,2581.9 h60
  text "X" at 12871.46,2581.9 h60
  text "V. SCORE" at 13049.46,2581.9 h60
  text "CERTIFICATION:" at 11122.46,2452.77 h60
  text "MATERIALS AND WORKMANSHIP FOR ALL PCBS" at 11847.46,2452.77 h60
  text "TO MEET OR EXCEED THE REQUIREMENTS OF:" at 11847.46,2358.71 h60
  text "X" at 11484.97,2230.08 h60
  text "ANSI IPC-A-600F CLASS ->" at 11612.96,2230.08 h60
  text "X" at 13260.97,2230.08 h60
  text "2" at 13370.96,2230.08 h60
  text "1" at 13055.96,2228.58 h60
  text "3" at 13724.96,2228.58 h60
  text "X" at 12296.97,2082.39 h60
  text "RoHS" at 12424.96,2082.39 h60
  text "OTHER" at 13069.36,2082.39 h60
  text "PER ORDER" at 13466.42,2082.39 h60
  text "ALL BOARDS MUST MEET OR EXCEED UL94-V0 REQUIREMENTS." at 11150,1928.57 h60
  text "PCB MUST BEAR THE UL94V-0 UL REGISTERED MATERIAL ID NUMBER" at 11150,1812.5 h60
  text "ADDITIONAL REQUIREMENTS:" at 11122.46,1643.08 h60
  text "MICROSECTION:" at 11197.23,1535.95 h60
  text "YES" at 12102.96,1535.95 h60
  text "REQUIRED" at 12964.46,1391.62 h60
  text "BARE BOARD ELEC. TEST:" at 11197.23,1388.76 h60
  text "NONE" at 12502.96,1388.76 h60
  text "X" at 12846.46,1388.76 h60
  text "PER ORDER" at 13556.46,1388.76 h60
  text "XX MIL VIAS REQUIRE NON-CONDUCTIVE FILL AND PLANARIZE" at 11365.38,1183.82 h59
  text "XX MIL VIAS REQUIRE CONDUCTIVE FILL AND PLANARIZE" at 11373.38,1079.84 h60
  text "OUTER XX MIL TRACES REQUIRE 50 OHM SINGLE-ENDED IMPEDANCE" at 11372.39,916.46 h58
  text "LAYER 2 & 3 (INNER LAYERS) XX MIL WIDE, XX MIL SPACE / TRACES REQUIRE 100 OHM DIFFERENTIAL IMPEDANCE" at 11364.39,680.74 h60
M11 Gerber Information:
  lines w10: -503,-1141.17 6097,-1141.17 ; -503,-937.83 6099,-937.83 ; -503,-734.5 -503,-1344.5 3502,-1344.5 6099,-1344.5 6099,-734.5 -502.5,-734.5 -502.5,-1344.5 1073,-1344.5 ; 1962,-1344.5 1962,-734.5 ; 3229,-937.83 3229,-734.5 ; 4069,-937.83 4069,-734.5 ; 4691,-1351 4691,-1148.17
  text "ALL ARTWORK VIEWED FROM TOP SIDE" at -439.5,-866.67 h60
  text "BOARD #:" at 2037,-866.67 h60
  text ".PRJ_Number" at 2582.5,-866.67 h60
  text "REV:" at 3427,-866.67 h60
  text ".PCB_Rev" at 3718.5,-866.67 h60
  text "SVN REV:" at 4265,-866.67 h60
  text ".VersionControl_RevNumber" at 4771,-866.67 h60
  text "LAYER NAME =" at -439.5,-1069.49 h60
  text "TID #:" at 2037,-1070 h60
  text ".TID" at 2582.5,-1070 h60
  text "PLOT NAME =" at -439.5,-1275.34 h60
  text ".plot_File_Name" at 366,-1275.34 h60
  text "GENERATED    :" at 2039,-1275.34 h60
  text ".Print_Date" at 2908.5,-1275.34 h60
  text ".Print_Time" at 3637.5,-1275.34 h60
  text "TEXAS INSTRUMENTS" at 4902,-1275.34 h60
M12 Stackup:
  drawing of 521 lines, arcs and shapes, not listed
  text "LAYER STACK-UP :" at 5845.47,5245.68 h80
  text "Layer" at 5895.54,4957.06 h55
  text "Name" at 6272.96,4957.06 h55
  text "Material" at 7126.89,4957.06 h55
  text "Thickness" at 7916.67,4957.06 h55
  text "Constant" at 8514.02,4957.06 h55
  text "Board Layer Stack" at 9038.06,4957.06 h55
  text "Top Overlay" at 6272.96,4847.06 h55
  text "Top Solder" at 6272.96,4737.06 h55
  text "Solder Resist" at 7126.89,4737.06 h55
  text "0.80mil" at 7916.67,4737.06 h55
  text "3.5" at 8514.02,4737.06 h55
  text "4" at 5725.88,4686 h60
  text "1" at 5895.54,4627.06 h55
  text "Top Layer" at 6272.96,4627.06 h55
  text "2.80mil" at 7916.67,4627.06 h55
  text "Dielectric 1" at 6272.96,4517.06 h55
  text "FR-4 High Tg" at 7126.89,4517.06 h55
  text "4.00mil" at 7916.67,4517.06 h55
  text "4.1" at 8514.02,4517.06 h55
  text "2" at 5895.54,4407.06 h55
  text "GND1" at 6272.96,4407.06 h55
  text "CF-004" at 7126.89,4407.06 h55
  text "1.40mil" at 7916.67,4407.06 h55
  text "Dielectric 2" at 6272.96,4297.06 h55
  text "FR-4 High Tg" at 7126.89,4297.06 h55
  text "8.00mil" at 7916.67,4297.06 h55
  text "4.1" at 8514.02,4297.06 h55
  text "4" at 5729.83,4246.99 h60
  text "3" at 5895.54,4187.06 h55
  text "SIGNAL1" at 6272.96,4187.06 h55
  text "CF-004" at 7126.89,4187.06 h55
  text "1.40mil" at 7916.67,4187.06 h55
  text "Dielectric 3" at 6272.96,4077.06 h55
  text "FR-4 High Tg" at 7126.89,4077.06 h55
  text "8.00mil" at 7916.67,4077.06 h55
  text "4.1" at 8514.02,4077.06 h55
  text "4" at 5895.54,3967.06 h55
  text "POWER1" at 6272.96,3967.06 h55
  text "CF-004" at 7126.89,3967.06 h55
  text "1.40mil" at 7916.67,3967.06 h55
  text "Dielectric 4" at 6272.96,3857.06 h55
  text "FR-4 High Tg" at 7126.89,3857.06 h55
  text "6.40mil" at 7916.67,3857.06 h55
  text "4.8" at 8514.02,3857.06 h55
  text "5" at 5895.54,3747.06 h55
  text "POWER2" at 6272.96,3747.06 h55
  text "CF-004" at 7126.89,3747.06 h55
  text "1.40mil" at 7916.67,3747.06 h55
  text "Dielectric 5" at 6272.96,3637.06 h55
  text "FR-4 High Tg" at 7126.89,3637.06 h55
  text "8.00mil" at 7916.67,3637.06 h55
  text "4.1" at 8514.02,3637.06 h55
  text "4" at 5731.44,3592.36 h60
  text "6" at 5895.54,3527.06 h55
  text "SIGNAL2" at 6272.96,3527.06 h55
  text "CF-004" at 7126.89,3527.06 h55
  text "1.40mil" at 7916.67,3527.06 h55
  text "Dielectric 6" at 6272.96,3417.06 h55
  text "FR-4 High Tg" at 7126.89,3417.06 h55
  text "8.00mil" at 7916.67,3417.06 h55
  text "4.1" at 8514.02,3417.06 h55
  text "7" at 5895.54,3307.06 h55
  text "GND2" at 6272.96,3307.06 h55
  text "CF-004" at 7126.89,3307.06 h55
  text "1.40mil" at 7916.67,3307.06 h55
  text "Dielectric 7" at 6272.96,3197.06 h55
  text "FR-4 High Tg" at 7126.89,3197.06 h55
  text "4.00mil" at 7916.67,3197.06 h55
  text "4.1" at 8514.02,3197.06 h55
  text "4" at 5728.68,3143.87 h60
  text "8" at 5895.54,3087.06 h55
  text "Bottom Layer" at 6272.96,3087.06 h55
  text "2.80mil" at 7916.67,3087.06 h55
  text "Bottom Solder" at 6272.96,2977.06 h55
  text "Solder Resist" at 7126.89,2977.06 h55
  text "0.80mil" at 7916.67,2977.06 h55
  text "3.5" at 8514.02,2977.06 h55
  text "Bottom Overlay" at 6272.96,2867.06 h55
  text "THIS IS AN IMPEDANCE CONTROLLED BOARD." at 6405.68,2676.09 h80
  text "NOTE :" at 5399.78,2633.46 h80
  text "1. ALL CORE AND PREPREG THICKNESSES ARE UP TO FAB SHOP TO SELECT." at 5410.27,2418.37 h80
  text "2. EXTERNAL LAYER CU THICKNESSES ARE FINISHED THICKNESS AFTER PLATING." at 5410.27,2212.01 h80
M13 Component Bodies Top:
  text ".Layer_Name" at 366,-1069.49 h60
M14 Component Bodies Bottom:
  text ".Layer_Name" at 366,-1069.49 h60
M15 Courtyards Top:
  text ".Layer_Name" at 366,-1069.49 h60
M16 Courtyards Bottom:
  text ".Layer_Name" at 366,-1069.49 h60
Drill Drawing:
  circle w10: c6205.2,289.86 r27.63
  lines w10: 5999.71,1326.4 6095.41,1326.4 6095.41,1417.96 5999.71,1417.96 5999.71,1326.4 ; 6001.12,1191.74 6096.82,1191.74 6096.82,1286.73 6001.12,1286.73 6001.12,1191.74 ; 6177.58,151.73 6191.39,151.73 6205.2,137.91 6219.02,151.73 6232.83,151.73 6219.02,165.54 6232.83,179.35 6219.02,179.35 6205.2,193.17 6191.39,179.35 6177.58,179.35 6191.39,165.54 6177.58,151.73 ; 6177.58,690.45 6232.83,690.45 6205.2,635.19 6177.58,690.45 ; 6177.58,1008.15 6232.83,1008.15 6232.83,1063.41 6177.58,1063.41 6177.58,1008.15
  lines w12: 6127.49,-520.98 10811.82,-520.98 ; 6127.49,1716.78 10811.82,1716.78 ; 6465.35,-645.3 6465.35,1841.1 ; 6797.35,-645.3 6797.35,1841.1 ; 7433.91,-645.3 7433.91,1841.1 ; 7693.05,-645.3 7693.05,1841.1 ; 8068.21,-645.3 8068.21,1841.1 ; 8792.54,-645.3 8792.54,1841.1 ; 9382.45,-645.3 9382.45,1841.1 ; 10059.97,-645.3 10059.97,1841.1 ; 6127.49,-645.3 10811.82,-645.3 10811.82,1841.1 6127.49,1841.1 6127.49,-645.3
  text "DRILL TABLE:" at 6129.79,1884.32 h80
  text "Symbol" at 6202.08,1754.07 h72
  text "Quantity" at 6502.64,1754.07 h72
  text "Finished Hole Size" at 6834.64,1754.07 h72
  text "Plated" at 7471.21,1754.07 h72
  text "Hole Type" at 7730.35,1754.07 h72
  text "Drill Layer Pair" at 8105.51,1754.07 h72
  text "Hole Length" at 8829.84,1754.07 h72
  text "Routed Path Length" at 9419.75,1754.07 h72
  text "Hole Tolerance (Mils)" at 10097.27,1754.07 h72
  text "43" at 6502.64,1629.75 h60
  text "7.87mil (0.200mm)" at 6834.64,1629.75 h60
  text "PTH" at 7471.21,1629.75 h60
  text "Round" at 7730.35,1629.75 h60
  text "Top Layer - Bottom Layer" at 8105.51,1629.75 h60
  text "-" at 8829.84,1629.75 h60
  text "-" at 9419.75,1629.75 h60
  text "+0.00/-7.874" at 10097.27,1629.75 h60
  text "A" at 6176.79,1619.76 h55.25
  text "126" at 6502.64,1505.43 h60
  text "8.00mil (0.203mm)" at 6834.64,1505.43 h60
  text "PTH" at 7471.21,1505.43 h60
  text "Round" at 7730.35,1505.43 h60
  text "Top Layer - Bottom Layer" at 8105.51,1505.43 h60
  text "-" at 8829.84,1505.43 h60
  text "-" at 9419.75,1505.43 h60
  text "+0.00/-8.00" at 10097.27,1505.43 h60
  text "C" at 6176.79,1495.44 h55.25
  text "63" at 6502.64,1381.11 h60
  text "8.01mil (0.203mm)" at 6834.64,1381.11 h60
  text "PTH" at 7471.21,1381.11 h60
  text "Round" at 7730.35,1381.11 h60
  text "Top Layer - Bottom Layer" at 8105.51,1381.11 h60
  text "-" at 8829.84,1381.11 h60
  text "-" at 9419.75,1381.11 h60
  text "+0.00/-8.01" at 10097.27,1381.11 h60
  text "D" at 6176.79,1371.12 h55.25
  text "6" at 6025.98,1348.47 h55
  text "22" at 6502.64,1256.79 h60
  text "8.02mil (0.204mm)" at 6834.64,1256.79 h60
  text "PTH" at 7471.21,1256.79 h60
  text "Round" at 7730.35,1256.79 h60
  text "Top Layer - Bottom Layer" at 8105.51,1256.79 h60
  text "-" at 8829.84,1256.79 h60
  text "-" at 9419.75,1256.79 h60
  text "+0.00/-8.02" at 10097.27,1256.79 h60
  text "B" at 6176.79,1246.8 h55.25
  text "5" at 6031.35,1213.23 h55
  text "593" at 6502.64,1132.47 h60
  text "10.00mil (0.254mm)" at 6834.64,1132.47 h60
  text "PTH" at 7471.21,1132.47 h60
  text "Round" at 7730.35,1132.47 h60
  text "Top Layer - Bottom Layer" at 8105.51,1132.47 h60
  text "-" at 8829.84,1132.47 h60
  text "-" at 9419.75,1132.47 h60
  text "+0.00/-10.00" at 10097.27,1132.47 h60
  text "E" at 6176.79,1122.48 h55.25
  text "6" at 6502.64,1008.15 h60
  text "12.99mil (0.330mm)" at 6834.64,1008.15 h60
  text "PTH" at 7471.21,1008.15 h60
  text "Round" at 7730.35,1008.15 h60
  text "Top Layer - Bottom Layer" at 8105.51,1008.15 h60
  text "-" at 8829.84,1008.15 h60
  text "-" at 9419.75,1008.15 h60
  text "12" at 6502.64,883.83 h60
  text "17.72mil (0.450mm)" at 6834.64,883.83 h60
  text "PTH" at 7471.21,883.83 h60
  text "Round" at 7730.35,883.83 h60
  text "Top Layer - Bottom Layer" at 8105.51,883.83 h60
  text "-" at 8829.84,883.83 h60
  text "-" at 9419.75,883.83 h60
  text "+/-3.00" at 10097.27,883.83 h60
  text "F" at 6176.79,873.84 h55.25
  text "4" at 6502.64,759.51 h60
  text "29.92mil (0.760mm)" at 6834.64,759.51 h60
  text "NPTH" at 7471.21,759.51 h60
  text "Round" at 7730.35,759.51 h60
  text "Top Layer - Bottom Layer" at 8105.51,759.51 h60
  text "-" at 8829.84,759.51 h60
  text "-" at 9419.75,759.51 h60
  text "+/-2.00" at 10097.27,759.51 h60
  text "G" at 6176.79,749.52 h55.25
  text "2" at 6502.64,635.19 h60
  text "29.92mil (0.760mm)" at 6834.64,635.19 h60
  text "PTH" at 7471.21,635.19 h60
  text "Rectangle" at 7730.35,635.19 h60
  text "Top Layer - Bottom Layer" at 8105.51,635.19 h60
  text "120.08mil (3.050mm)" at 8829.84,635.19 h60
  text "120.08mil (3.050mm)" at 9419.75,635.19 h60
  text "15" at 6502.64,510.87 h60
  text "40.00mil (1.016mm)" at 6834.64,510.87 h60
  text "PTH" at 7471.21,510.87 h60
  text "Round" at 7730.35,510.87 h60
  text "Top Layer - Bottom Layer" at 8105.51,510.87 h60
  text "-" at 8829.84,510.87 h60
  text "-" at 9419.75,510.87 h60
  text "+/-3.00" at 10097.27,510.87 h60
  text "H" at 6176.79,500.88 h55.25
  text "12" at 6502.64,386.55 h60
  text "40.16mil (1.020mm)" at 6834.64,386.55 h60
  text "PTH" at 7471.21,386.55 h60
  text "Round" at 7730.35,386.55 h60
  text "Top Layer - Bottom Layer" at 8105.51,386.55 h60
  text "-" at 8829.84,386.55 h60
  text "-" at 9419.75,386.55 h60
  text "+/-3.00" at 10097.27,386.55 h60
  text "I" at 6186,376.56 h55.25
  text "1" at 6502.64,262.23 h60
  text "40.16mil (1.020mm)" at 6834.64,262.23 h60
  text "PTH" at 7471.21,262.23 h60
  text "Rectangle" at 7730.35,262.23 h60
  text "Top Layer - Bottom Layer" at 8105.51,262.23 h60
  text "140.16mil (3.560mm)" at 8829.84,262.23 h60
  text "140.16mil (3.560mm)" at 9419.75,262.23 h60
  text "10" at 6502.64,137.91 h60
  text "44.88mil (1.140mm)" at 6834.64,137.91 h60
  text "PTH" at 7471.21,137.91 h60
  text "Round" at 7730.35,137.91 h60
  text "Top Layer - Bottom Layer" at 8105.51,137.91 h60
  text "-" at 8829.84,137.91 h60
  text "-" at 9419.75,137.91 h60
  text "4" at 6502.64,13.59 h60
  text "70.87mil (1.800mm)" at 6834.64,13.59 h60
  text "PTH" at 7471.21,13.59 h60
  text "Round" at 7730.35,13.59 h60
  text "Top Layer - Bottom Layer" at 8105.51,13.59 h60
  text "-" at 8829.84,13.59 h60
  text "-" at 9419.75,13.59 h60
  text "+/-3.00" at 10097.27,13.59 h60
  text "K" at 6176.79,3.6 h55.25
  text "4" at 6502.64,-110.73 h60
  text "92.52mil (2.350mm)" at 6834.64,-110.73 h60
  text "NPTH" at 7471.21,-110.73 h60
  text "Round" at 7730.35,-110.73 h60
  text "Top Layer - Bottom Layer" at 8105.51,-110.73 h60
  text "-" at 8829.84,-110.73 h60
  text "-" at 9419.75,-110.73 h60
  text "+/-2.00" at 10097.27,-110.73 h60
  text "M" at 6176.79,-120.72 h55.25
  text "1" at 6502.64,-235.05 h60
  text "94.49mil (2.400mm)" at 6834.64,-235.05 h60
  text "NPTH" at 7471.21,-235.05 h60
  text "Round" at 7730.35,-235.05 h60
  text "Top Layer - Bottom Layer" at 8105.51,-235.05 h60
  text "-" at 8829.84,-235.05 h60
  text "-" at 9419.75,-235.05 h60
  text "+/-2.00" at 10097.27,-235.05 h60
  text "R" at 6176.79,-245.04 h55.25
  text "1" at 6502.64,-359.37 h60
  text "94.49mil (2.400mm)" at 6834.64,-359.37 h60
  text "NPTH" at 7471.21,-359.37 h60
  text "Slot" at 7730.35,-359.37 h60
  text "Top Layer - Bottom Layer" at 8105.51,-359.37 h60
  text "116.14mil (2.950mm)" at 8829.84,-359.37 h60
  text "21.65mil (0.550mm)" at 9419.75,-359.37 h60
  text "+/-2.00" at 10097.27,-359.37 h60
  text "N" at 6176.79,-369.36 h55.25
  text "4" at 6502.64,-483.69 h60
  text "125.98mil (3.200mm)" at 6834.64,-483.69 h60
  text "PTH" at 7471.21,-483.69 h60
  text "Round" at 7730.35,-483.69 h60
  text "Top Layer - Bottom Layer" at 8105.51,-483.69 h60
  text "-" at 8829.84,-483.69 h60
  text "-" at 9419.75,-483.69 h60
  text "+/-3.00" at 10097.27,-483.69 h60
  text "P" at 6176.79,-493.68 h55.25
  text "923 Total" at 6502.64,-608.01 h60
  text "Slot definitions :" at 6202.08,-695.03 h60
  text "Routed Path Length" at 6652.79,-695.03 h60
  text "= Calculated from tool start centre position to tool end centre position." at 7192.53,-695.03 h60
  text "Hole Length" at 6652.79,-744.76 h60
  text "= Routed Path Length + Tool Size = Slot length as defined in the PCB layout" at 6992.73,-744.76 h60
  text "FAB" at 366,-1069.49 h60
M17 Embedded Cavity:
  text ".Layer_Name" at 366,-1069.49 h60
M18 Embedded Assembly:
  text ".Layer_Name" at 366,-1069.49 h60
M19 Embedded Keepout:
  text ".Layer_Name" at 366,-1069.49 h60

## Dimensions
0,0 to 4739,-211 on M2 Board Dimensions
0,0 to -211,2948.45 on M2 Board Dimensions
0,0 to -211,-211 on M2 Board Dimensions
0,0 to -211,-211 on M2 Board Dimensions
0,0 to 55.19,-278.4 on M2 Board Dimensions
4839.9,-272.52 to 5839.9,-272.52 on M2 Board Dimensions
